VERSION 5.8 ;
BUSBITCHARS "[]" ;
DIVIDERCHAR "/" ;
UNITS
    DATABASE MICRONS 1000 ;
END UNITS

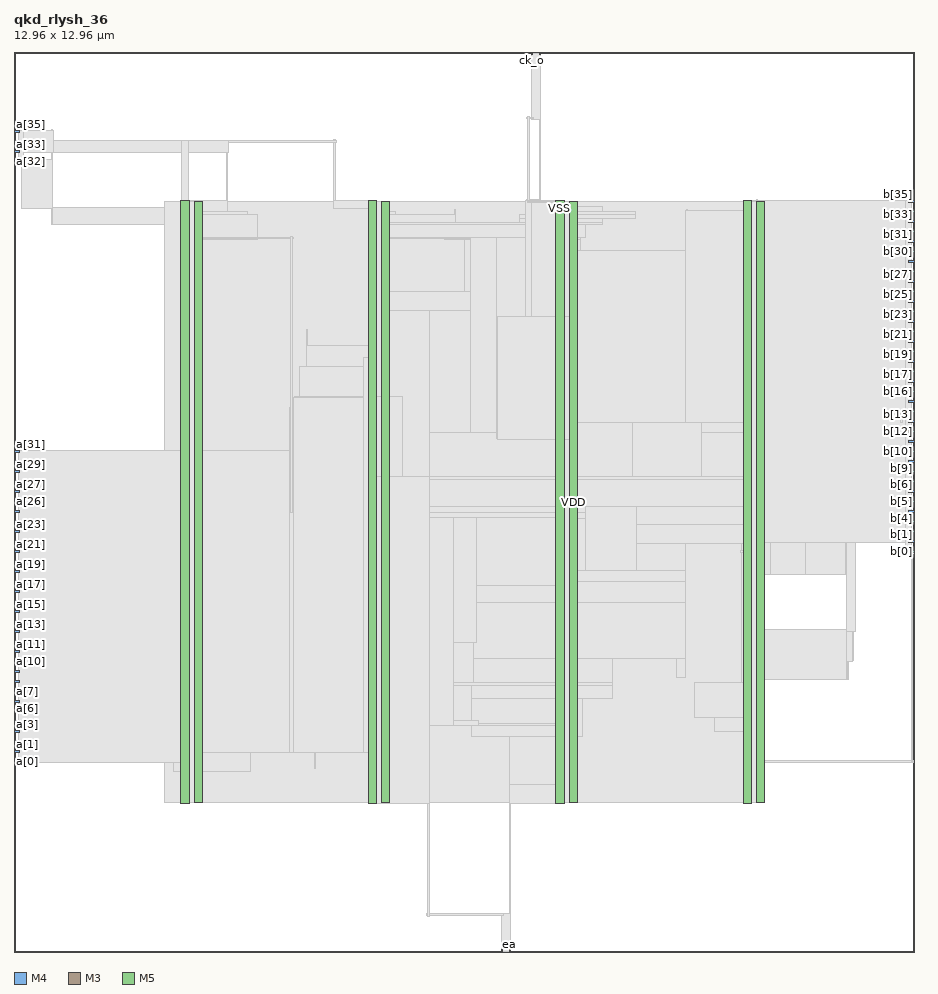
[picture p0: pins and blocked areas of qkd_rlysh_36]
MACRO qkd_rlysh_36
  FOREIGN qkd_rlysh_36 0 0 ;
  CLASS BLOCK ;
  SIZE 12.96 BY 12.96 ;
  PIN a[0]
    DIRECTION INPUT ;
    USE SIGNAL ;
    PORT
      LAYER M4 ;
        RECT  0 2.736 0.084 2.76 ;
    END
  END a[0]
  PIN a[10]
    DIRECTION INPUT ;
    USE SIGNAL ;
    PORT
      LAYER M4 ;
        RECT  0 4.176 0.084 4.2 ;
    END
  END a[10]
  PIN a[11]
    DIRECTION INPUT ;
    USE SIGNAL ;
    PORT
      LAYER M4 ;
        RECT  0 4.32 0.084 4.344 ;
    END
  END a[11]
  PIN a[12]
    DIRECTION INPUT ;
    USE SIGNAL ;
    PORT
      LAYER M4 ;
        RECT  0 4.464 0.084 4.488 ;
    END
  END a[12]
  PIN a[13]
    DIRECTION INPUT ;
    USE SIGNAL ;
    PORT
      LAYER M4 ;
        RECT  0 4.608 0.084 4.632 ;
    END
  END a[13]
  PIN a[14]
    DIRECTION INPUT ;
    USE SIGNAL ;
    PORT
      LAYER M4 ;
        RECT  0 4.752 0.084 4.776 ;
    END
  END a[14]
  PIN a[15]
    DIRECTION INPUT ;
    USE SIGNAL ;
    PORT
      LAYER M4 ;
        RECT  0 4.896 0.084 4.92 ;
    END
  END a[15]
  PIN a[16]
    DIRECTION INPUT ;
    USE SIGNAL ;
    PORT
      LAYER M4 ;
        RECT  0 5.04 0.084 5.064 ;
    END
  END a[16]
  PIN a[17]
    DIRECTION INPUT ;
    USE SIGNAL ;
    PORT
      LAYER M4 ;
        RECT  0 5.184 0.084 5.208 ;
    END
  END a[17]
  PIN a[18]
    DIRECTION INPUT ;
    USE SIGNAL ;
    PORT
      LAYER M4 ;
        RECT  0 5.328 0.084 5.352 ;
    END
  END a[18]
  PIN a[19]
    DIRECTION INPUT ;
    USE SIGNAL ;
    PORT
      LAYER M4 ;
        RECT  0 5.472 0.084 5.496 ;
    END
  END a[19]
  PIN a[1]
    DIRECTION INPUT ;
    USE SIGNAL ;
    PORT
      LAYER M4 ;
        RECT  0 2.88 0.084 2.904 ;
    END
  END a[1]
  PIN a[20]
    DIRECTION INPUT ;
    USE SIGNAL ;
    PORT
      LAYER M4 ;
        RECT  0 5.616 0.084 5.64 ;
    END
  END a[20]
  PIN a[21]
    DIRECTION INPUT ;
    USE SIGNAL ;
    PORT
      LAYER M4 ;
        RECT  0 5.76 0.084 5.784 ;
    END
  END a[21]
  PIN a[22]
    DIRECTION INPUT ;
    USE SIGNAL ;
    PORT
      LAYER M4 ;
        RECT  0 5.904 0.084 5.928 ;
    END
  END a[22]
  PIN a[23]
    DIRECTION INPUT ;
    USE SIGNAL ;
    PORT
      LAYER M4 ;
        RECT  0 6.048 0.084 6.072 ;
    END
  END a[23]
  PIN a[24]
    DIRECTION INPUT ;
    USE SIGNAL ;
    PORT
      LAYER M4 ;
        RECT  0 6.192 0.084 6.216 ;
    END
  END a[24]
  PIN a[25]
    DIRECTION INPUT ;
    USE SIGNAL ;
    PORT
      LAYER M4 ;
        RECT  0 6.336 0.084 6.36 ;
    END
  END a[25]
  PIN a[26]
    DIRECTION INPUT ;
    USE SIGNAL ;
    PORT
      LAYER M4 ;
        RECT  0 6.48 0.084 6.504 ;
    END
  END a[26]
  PIN a[27]
    DIRECTION INPUT ;
    USE SIGNAL ;
    PORT
      LAYER M4 ;
        RECT  0 6.624 0.084 6.648 ;
    END
  END a[27]
  PIN a[28]
    DIRECTION INPUT ;
    USE SIGNAL ;
    PORT
      LAYER M4 ;
        RECT  0 6.768 0.084 6.792 ;
    END
  END a[28]
  PIN a[29]
    DIRECTION INPUT ;
    USE SIGNAL ;
    PORT
      LAYER M4 ;
        RECT  0 6.912 0.084 6.936 ;
    END
  END a[29]
  PIN a[2]
    DIRECTION INPUT ;
    USE SIGNAL ;
    PORT
      LAYER M4 ;
        RECT  0 3.024 0.084 3.048 ;
    END
  END a[2]
  PIN a[30]
    DIRECTION INPUT ;
    USE SIGNAL ;
    PORT
      LAYER M4 ;
        RECT  0 7.056 0.084 7.08 ;
    END
  END a[30]
  PIN a[31]
    DIRECTION INPUT ;
    USE SIGNAL ;
    PORT
      LAYER M4 ;
        RECT  0 7.2 0.084 7.224 ;
    END
  END a[31]
  PIN a[32]
    DIRECTION INPUT ;
    USE SIGNAL ;
    PORT
      LAYER M4 ;
        RECT  0 11.376 0.084 11.4 ;
    END
  END a[32]
  PIN a[33]
    DIRECTION INPUT ;
    USE SIGNAL ;
    PORT
      LAYER M4 ;
        RECT  0 11.52 0.084 11.544 ;
    END
  END a[33]
  PIN a[34]
    DIRECTION INPUT ;
    USE SIGNAL ;
    PORT
      LAYER M4 ;
        RECT  0 11.664 0.084 11.688 ;
    END
  END a[34]
  PIN a[35]
    DIRECTION INPUT ;
    USE SIGNAL ;
    PORT
      LAYER M4 ;
        RECT  0 11.808 0.084 11.832 ;
    END
  END a[35]
  PIN a[3]
    DIRECTION INPUT ;
    USE SIGNAL ;
    PORT
      LAYER M4 ;
        RECT  0 3.168 0.084 3.192 ;
    END
  END a[3]
  PIN a[4]
    DIRECTION INPUT ;
    USE SIGNAL ;
    PORT
      LAYER M4 ;
        RECT  0 3.312 0.084 3.336 ;
    END
  END a[4]
  PIN a[5]
    DIRECTION INPUT ;
    USE SIGNAL ;
    PORT
      LAYER M4 ;
        RECT  0 3.456 0.084 3.48 ;
    END
  END a[5]
  PIN a[6]
    DIRECTION INPUT ;
    USE SIGNAL ;
    PORT
      LAYER M4 ;
        RECT  0 3.6 0.084 3.624 ;
    END
  END a[6]
  PIN a[7]
    DIRECTION INPUT ;
    USE SIGNAL ;
    PORT
      LAYER M4 ;
        RECT  0 3.744 0.084 3.768 ;
    END
  END a[7]
  PIN a[8]
    DIRECTION INPUT ;
    USE SIGNAL ;
    PORT
      LAYER M4 ;
        RECT  0 3.888 0.084 3.912 ;
    END
  END a[8]
  PIN a[9]
    DIRECTION INPUT ;
    USE SIGNAL ;
    PORT
      LAYER M4 ;
        RECT  0 4.032 0.084 4.056 ;
    END
  END a[9]
  PIN b[0]
    DIRECTION OUTPUT ;
    USE SIGNAL ;
    PORT
      LAYER M4 ;
        RECT  12.876 5.76 12.96 5.784 ;
    END
  END b[0]
  PIN b[10]
    DIRECTION OUTPUT ;
    USE SIGNAL ;
    PORT
      LAYER M4 ;
        RECT  12.876 7.2 12.96 7.224 ;
    END
  END b[10]
  PIN b[11]
    DIRECTION OUTPUT ;
    USE SIGNAL ;
    PORT
      LAYER M4 ;
        RECT  12.876 7.344 12.96 7.368 ;
    END
  END b[11]
  PIN b[12]
    DIRECTION OUTPUT ;
    USE SIGNAL ;
    PORT
      LAYER M4 ;
        RECT  12.876 7.488 12.96 7.512 ;
    END
  END b[12]
  PIN b[13]
    DIRECTION OUTPUT ;
    USE SIGNAL ;
    PORT
      LAYER M4 ;
        RECT  12.876 7.632 12.96 7.656 ;
    END
  END b[13]
  PIN b[14]
    DIRECTION OUTPUT ;
    USE SIGNAL ;
    PORT
      LAYER M4 ;
        RECT  12.876 7.776 12.96 7.8 ;
    END
  END b[14]
  PIN b[15]
    DIRECTION OUTPUT ;
    USE SIGNAL ;
    PORT
      LAYER M4 ;
        RECT  12.876 7.92 12.96 7.944 ;
    END
  END b[15]
  PIN b[16]
    DIRECTION OUTPUT ;
    USE SIGNAL ;
    PORT
      LAYER M4 ;
        RECT  12.876 8.064 12.96 8.088 ;
    END
  END b[16]
  PIN b[17]
    DIRECTION OUTPUT ;
    USE SIGNAL ;
    PORT
      LAYER M4 ;
        RECT  12.876 8.208 12.96 8.232 ;
    END
  END b[17]
  PIN b[18]
    DIRECTION OUTPUT ;
    USE SIGNAL ;
    PORT
      LAYER M4 ;
        RECT  12.876 8.352 12.96 8.376 ;
    END
  END b[18]
  PIN b[19]
    DIRECTION OUTPUT ;
    USE SIGNAL ;
    PORT
      LAYER M4 ;
        RECT  12.876 8.496 12.96 8.52 ;
    END
  END b[19]
  PIN b[1]
    DIRECTION OUTPUT ;
    USE SIGNAL ;
    PORT
      LAYER M4 ;
        RECT  12.876 5.904 12.96 5.928 ;
    END
  END b[1]
  PIN b[20]
    DIRECTION OUTPUT ;
    USE SIGNAL ;
    PORT
      LAYER M4 ;
        RECT  12.876 8.64 12.96 8.664 ;
    END
  END b[20]
  PIN b[21]
    DIRECTION OUTPUT ;
    USE SIGNAL ;
    PORT
      LAYER M4 ;
        RECT  12.876 8.784 12.96 8.808 ;
    END
  END b[21]
  PIN b[22]
    DIRECTION OUTPUT ;
    USE SIGNAL ;
    PORT
      LAYER M4 ;
        RECT  12.876 8.928 12.96 8.952 ;
    END
  END b[22]
  PIN b[23]
    DIRECTION OUTPUT ;
    USE SIGNAL ;
    PORT
      LAYER M4 ;
        RECT  12.876 9.072 12.96 9.096 ;
    END
  END b[23]
  PIN b[24]
    DIRECTION OUTPUT ;
    USE SIGNAL ;
    PORT
      LAYER M4 ;
        RECT  12.876 9.216 12.96 9.24 ;
    END
  END b[24]
  PIN b[25]
    DIRECTION OUTPUT ;
    USE SIGNAL ;
    PORT
      LAYER M4 ;
        RECT  12.876 9.36 12.96 9.384 ;
    END
  END b[25]
  PIN b[26]
    DIRECTION OUTPUT ;
    USE SIGNAL ;
    PORT
      LAYER M4 ;
        RECT  12.876 9.504 12.96 9.528 ;
    END
  END b[26]
  PIN b[27]
    DIRECTION OUTPUT ;
    USE SIGNAL ;
    PORT
      LAYER M4 ;
        RECT  12.876 9.648 12.96 9.672 ;
    END
  END b[27]
  PIN b[28]
    DIRECTION OUTPUT ;
    USE SIGNAL ;
    PORT
      LAYER M4 ;
        RECT  12.876 9.792 12.96 9.816 ;
    END
  END b[28]
  PIN b[29]
    DIRECTION OUTPUT ;
    USE SIGNAL ;
    PORT
      LAYER M4 ;
        RECT  12.876 9.936 12.96 9.96 ;
    END
  END b[29]
  PIN b[2]
    DIRECTION OUTPUT ;
    USE SIGNAL ;
    PORT
      LAYER M4 ;
        RECT  12.876 6.048 12.96 6.072 ;
    END
  END b[2]
  PIN b[30]
    DIRECTION OUTPUT ;
    USE SIGNAL ;
    PORT
      LAYER M4 ;
        RECT  12.876 10.08 12.96 10.104 ;
    END
  END b[30]
  PIN b[31]
    DIRECTION OUTPUT ;
    USE SIGNAL ;
    PORT
      LAYER M4 ;
        RECT  12.876 10.224 12.96 10.248 ;
    END
  END b[31]
  PIN b[32]
    DIRECTION OUTPUT ;
    USE SIGNAL ;
    PORT
      LAYER M4 ;
        RECT  12.876 10.368 12.96 10.392 ;
    END
  END b[32]
  PIN b[33]
    DIRECTION OUTPUT ;
    USE SIGNAL ;
    PORT
      LAYER M4 ;
        RECT  12.876 10.512 12.96 10.536 ;
    END
  END b[33]
  PIN b[34]
    DIRECTION OUTPUT ;
    USE SIGNAL ;
    PORT
      LAYER M4 ;
        RECT  12.876 10.656 12.96 10.68 ;
    END
  END b[34]
  PIN b[35]
    DIRECTION OUTPUT ;
    USE SIGNAL ;
    PORT
      LAYER M4 ;
        RECT  12.876 10.8 12.96 10.824 ;
    END
  END b[35]
  PIN b[3]
    DIRECTION OUTPUT ;
    USE SIGNAL ;
    PORT
      LAYER M4 ;
        RECT  12.876 6.192 12.96 6.216 ;
    END
  END b[3]
  PIN b[4]
    DIRECTION OUTPUT ;
    USE SIGNAL ;
    PORT
      LAYER M4 ;
        RECT  12.876 6.336 12.96 6.36 ;
    END
  END b[4]
  PIN b[5]
    DIRECTION OUTPUT ;
    USE SIGNAL ;
    PORT
      LAYER M4 ;
        RECT  12.876 6.48 12.96 6.504 ;
    END
  END b[5]
  PIN b[6]
    DIRECTION OUTPUT ;
    USE SIGNAL ;
    PORT
      LAYER M4 ;
        RECT  12.876 6.624 12.96 6.648 ;
    END
  END b[6]
  PIN b[7]
    DIRECTION OUTPUT ;
    USE SIGNAL ;
    PORT
      LAYER M4 ;
        RECT  12.876 6.768 12.96 6.792 ;
    END
  END b[7]
  PIN b[8]
    DIRECTION OUTPUT ;
    USE SIGNAL ;
    PORT
      LAYER M4 ;
        RECT  12.876 6.912 12.96 6.936 ;
    END
  END b[8]
  PIN b[9]
    DIRECTION OUTPUT ;
    USE SIGNAL ;
    PORT
      LAYER M4 ;
        RECT  12.876 7.056 12.96 7.08 ;
    END
  END b[9]
  PIN ck_o
    DIRECTION OUTPUT ;
    USE SIGNAL ;
    PORT
      LAYER M3 ;
        RECT  7.452 12.923 7.47 12.96 ;
    END
  END ck_o
  PIN ckf
    DIRECTION INPUT ;
    USE SIGNAL ;
    PORT
      LAYER M3 ;
        RECT  7.02 0 7.038 0.037 ;
    END
  END ckf
  PIN ea
    DIRECTION INPUT ;
    USE SIGNAL ;
    PORT
      LAYER M3 ;
        RECT  7.128 0 7.146 0.037 ;
    END
  END ea
  PIN eb
    DIRECTION OUTPUT ;
    USE SIGNAL ;
    PORT
      LAYER M3 ;
        RECT  7.56 12.923 7.578 12.96 ;
    END
  END eb
  PIN VDD
    DIRECTION INOUT ;
    USE POWER ;
    PORT
      LAYER M5 ;
        RECT  10.692 2.151 10.812 10.809 ;
        RECT  7.992 2.151 8.112 10.809 ;
        RECT  5.292 2.151 5.412 10.809 ;
        RECT  2.592 2.151 2.712 10.809 ;
    END
  END VDD
  PIN VSS
    DIRECTION INOUT ;
    USE GROUND ;
    PORT
      LAYER M5 ;
        RECT  10.5 2.137 10.62 10.823 ;
        RECT  7.8 2.137 7.92 10.823 ;
        RECT  5.1 2.137 5.22 10.823 ;
        RECT  2.4 2.137 2.52 10.823 ;
    END
  END VSS
  OBS
    LAYER RVTN ;
     RECT  2.16 2.16 10.8 2.295 ;
     RECT  2.16 2.565 10.8 2.835 ;
     RECT  2.16 3.105 10.8 3.375 ;
     RECT  2.16 3.645 10.8 3.915 ;
     RECT  2.16 4.185 10.8 4.455 ;
     RECT  2.16 4.725 10.8 4.995 ;
     RECT  2.16 5.265 10.8 5.535 ;
     RECT  2.16 5.805 10.8 6.075 ;
     RECT  2.16 6.345 10.8 6.615 ;
     RECT  2.16 6.885 10.8 7.155 ;
     RECT  2.16 7.425 10.8 7.695 ;
     RECT  2.16 7.965 10.8 8.235 ;
     RECT  2.16 8.505 10.8 8.775 ;
     RECT  2.16 9.045 10.8 9.315 ;
     RECT  2.16 9.585 10.8 9.855 ;
     RECT  2.16 10.125 10.8 10.395 ;
     RECT  2.16 10.665 10.8 10.8 ;
    LAYER RVTP ;
     RECT  2.16 2.295 10.8 2.565 ;
     RECT  2.16 2.835 10.8 3.105 ;
     RECT  2.16 3.375 10.8 3.645 ;
     RECT  2.16 3.915 10.8 4.185 ;
     RECT  2.16 4.455 10.8 4.725 ;
     RECT  2.16 4.995 10.8 5.265 ;
     RECT  2.16 5.535 10.8 5.805 ;
     RECT  2.16 6.075 10.8 6.345 ;
     RECT  2.16 6.615 10.8 6.885 ;
     RECT  2.16 7.155 10.8 7.425 ;
     RECT  2.16 7.695 10.8 7.965 ;
     RECT  2.16 8.235 10.8 8.505 ;
     RECT  2.16 8.775 10.8 9.045 ;
     RECT  2.16 9.315 10.8 9.585 ;
     RECT  2.16 9.855 10.8 10.125 ;
     RECT  2.16 10.395 10.8 10.665 ;
    LAYER M1 ;
     RECT  2.16 2.151 10.8 10.809 ;
    LAYER M2 ;
     RECT  0.103 10.71 0.535 10.728 ;
     RECT  0.103 5.274 2.16 5.292 ;
     RECT  0.535 6.822 2.16 6.84 ;
     RECT  0.535 10.476 2.16 10.728 ;
     RECT  2.16 2.151 10.8 10.809 ;
     RECT  10.8 2.421 10.812 10.539 ;
     RECT  10.812 5.436 10.895 10.494 ;
     RECT  10.895 5.436 11.399 9.504 ;
     RECT  11.399 5.436 11.975 6.102 ;
     RECT  10.812 3.924 12.011 4.644 ;
     RECT  11.399 6.966 12.011 9.504 ;
     RECT  10.895 10.368 12.011 10.494 ;
     RECT  11.975 5.436 12.047 5.454 ;
     RECT  12.011 6.966 12.047 7.722 ;
     RECT  12.011 8.676 12.047 9.504 ;
     RECT  12.011 4.194 12.083 4.644 ;
     RECT  12.047 9.396 12.083 9.414 ;
     RECT  12.083 4.626 12.119 4.644 ;
     RECT  12.047 6.966 12.875 6.984 ;
     RECT  10.812 2.736 12.947 2.754 ;
     RECT  12.847 5.742 12.947 5.76 ;
    LAYER M3 ;
     RECT  7.02 0.012 7.146 0.557 ;
     RECT  7.128 0.557 7.146 2.143 ;
     RECT  2.415 2.143 2.505 2.413 ;
     RECT  5.115 2.143 5.205 2.413 ;
     RECT  7.128 2.143 7.905 2.413 ;
     RECT  10.515 2.143 10.605 2.413 ;
     RECT  2.415 2.413 2.697 2.605 ;
     RECT  4.32 2.641 4.338 2.875 ;
     RECT  4.14 2.875 4.338 3.065 ;
     RECT  4.248 3.065 4.338 3.109 ;
     RECT  5.115 2.413 5.397 3.109 ;
     RECT  7.128 2.413 8.097 3.109 ;
     RECT  10.515 2.413 10.797 3.181 ;
     RECT  4.248 3.109 5.814 3.335 ;
     RECT  10.08 3.181 10.797 3.379 ;
     RECT  2.304 2.605 3.402 3.488 ;
     RECT  6.588 3.109 8.19 3.649 ;
     RECT  2.34 3.488 3.402 3.749 ;
     RECT  6.588 3.649 8.622 3.835 ;
     RECT  0.144 3.739 0.162 3.869 ;
     RECT  6.3 3.835 8.622 3.875 ;
     RECT  9.792 3.379 10.797 3.875 ;
     RECT  4.284 3.335 5.397 4.109 ;
     RECT  11.988 3.919 12.006 4.189 ;
     RECT  6.624 3.875 8.622 4.225 ;
     RECT  9.54 3.955 9.666 4.225 ;
     RECT  2.34 3.749 3.258 4.315 ;
     RECT  11.988 4.189 12.078 4.621 ;
     RECT  2.304 4.315 3.258 4.801 ;
     RECT  4.32 4.109 5.397 4.801 ;
     RECT  2.304 4.801 3.51 4.919 ;
     RECT  4.32 4.801 5.526 5.029 ;
     RECT  6.624 4.225 9.666 5.029 ;
     RECT  0.108 4.891 0.126 5.227 ;
     RECT  0.108 5.227 0.162 5.297 ;
     RECT  4.32 5.029 9.666 5.341 ;
     RECT  4.176 5.341 9.666 5.495 ;
     RECT  12.924 2.731 12.942 5.737 ;
     RECT  2.304 4.919 3.258 5.765 ;
     RECT  12.852 5.737 12.942 5.765 ;
     RECT  12.852 5.765 12.87 5.789 ;
     RECT  8.964 5.495 9.666 5.881 ;
     RECT  10.476 3.875 10.797 5.881 ;
     RECT  11.988 4.621 12.114 6.076 ;
     RECT  8.964 5.881 10.797 6.151 ;
     RECT  11.952 6.076 12.114 6.151 ;
     RECT  4.176 5.495 8.226 6.241 ;
     RECT  0.144 5.297 0.162 6.283 ;
     RECT  2.412 5.765 3.258 6.305 ;
     RECT  2.415 6.305 3.258 6.331 ;
     RECT  4.104 6.241 8.226 6.331 ;
     RECT  2.415 6.331 8.226 6.421 ;
     RECT  8.964 6.151 12.114 6.421 ;
     RECT  0.144 6.283 0.198 6.509 ;
     RECT  0.18 6.509 0.198 6.653 ;
     RECT  2.415 6.421 12.114 6.809 ;
     RECT  4.104 6.809 12.114 6.845 ;
     RECT  0.54 6.817 0.558 6.941 ;
     RECT  12.852 6.907 12.87 6.989 ;
     RECT  2.415 6.809 3.366 7.051 ;
     RECT  2.304 7.051 3.366 7.088 ;
     RECT  2.415 7.088 3.366 7.115 ;
     RECT  9.9 6.845 12.114 7.483 ;
     RECT  9.9 7.483 12.69 7.619 ;
     RECT  10.515 7.619 12.69 7.661 ;
     RECT  10.515 7.661 12.042 7.805 ;
     RECT  4.104 6.845 8.91 7.897 ;
     RECT  4.032 7.897 8.91 7.997 ;
     RECT  10.515 7.805 10.89 8.381 ;
     RECT  4.104 7.997 8.91 8.429 ;
     RECT  4.212 8.429 8.91 8.735 ;
     RECT  5.115 8.735 8.91 8.851 ;
     RECT  4.212 8.735 4.23 8.969 ;
     RECT  5.115 8.851 9.054 9.013 ;
     RECT  5.115 9.013 9.162 9.041 ;
     RECT  8.892 9.041 9.162 9.113 ;
     RECT  10.515 8.381 10.818 9.113 ;
     RECT  12.78 8.539 12.798 9.341 ;
     RECT  11.988 7.805 12.042 9.391 ;
     RECT  5.115 9.041 8.154 9.509 ;
     RECT  11.988 9.391 12.078 9.533 ;
     RECT  8.892 9.113 8.982 9.545 ;
     RECT  8.964 9.545 8.982 9.815 ;
     RECT  12.024 9.533 12.078 9.821 ;
     RECT  10.515 9.113 10.797 9.925 ;
     RECT  10.515 9.925 10.89 9.965 ;
     RECT  10.515 9.965 10.818 10.253 ;
     RECT  2.415 7.115 2.697 10.267 ;
     RECT  6.48 9.509 8.154 10.267 ;
     RECT  5.115 9.509 5.397 10.291 ;
     RECT  6.192 10.267 8.154 10.291 ;
     RECT  5.115 10.291 8.226 10.471 ;
     RECT  5.115 10.471 8.478 10.499 ;
     RECT  11.988 10.357 12.006 10.541 ;
     RECT  10.515 10.253 10.797 10.547 ;
     RECT  7.272 10.499 8.478 10.561 ;
     RECT  2.415 10.267 3.51 10.625 ;
     RECT  5.115 10.499 6.354 10.625 ;
     RECT  7.272 10.561 8.946 10.625 ;
     RECT  2.415 10.625 3.366 10.661 ;
     RECT  5.115 10.625 5.49 10.661 ;
     RECT  7.38 10.625 8.946 10.661 ;
     RECT  9.684 10.291 9.702 10.685 ;
     RECT  6.336 10.625 6.354 10.697 ;
     RECT  0.54 10.471 0.558 10.705 ;
     RECT  5.115 10.661 5.205 10.705 ;
     RECT  7.38 10.661 8.478 10.733 ;
     RECT  2.415 10.661 3.078 10.817 ;
     RECT  4.608 10.705 5.205 10.817 ;
     RECT  7.38 10.733 7.905 10.817 ;
     RECT  10.515 10.547 10.71 10.817 ;
     RECT  7.38 10.817 7.578 10.829 ;
     RECT  10.692 10.817 10.71 10.829 ;
     RECT  0.108 10.705 0.558 11.405 ;
     RECT  3.06 10.817 3.078 11.549 ;
     RECT  4.608 10.817 4.626 11.693 ;
     RECT  0.54 11.405 0.558 11.837 ;
     RECT  7.56 10.829 7.578 11.995 ;
     RECT  7.452 11.995 7.578 12.941 ;
    LAYER M4 ;
     RECT  0.06 11.376 0.137 11.832 ;
     RECT  0.137 11.52 0.569 11.832 ;
     RECT  0.06 2.736 2.408 7.224 ;
     RECT  0.569 11.52 2.408 11.688 ;
     RECT  2.408 2.148 2.512 11.688 ;
     RECT  2.512 2.418 2.704 10.542 ;
     RECT  2.512 11.52 3.089 11.688 ;
     RECT  2.704 2.88 3.973 7.224 ;
     RECT  2.704 10.272 4.019 10.296 ;
     RECT  3.973 2.88 4.021 7.848 ;
     RECT  3.089 11.664 4.637 11.688 ;
     RECT  4.021 2.88 5.029 7.992 ;
     RECT  5.029 2.88 5.108 8.568 ;
     RECT  5.108 2.148 5.212 10.812 ;
     RECT  5.212 2.418 5.404 10.542 ;
     RECT  5.404 3.264 5.987 9.24 ;
     RECT  5.987 3.264 6.329 6.264 ;
     RECT  5.987 7.488 6.577 9.24 ;
     RECT  5.404 10.272 6.577 10.296 ;
     RECT  6.329 4.464 6.653 6.264 ;
     RECT  6.329 3.264 6.689 3.336 ;
     RECT  6.577 7.488 6.949 10.296 ;
     RECT  5.941 0.528 7.049 0.552 ;
     RECT  6.949 7.392 7.369 10.296 ;
     RECT  7.369 7.392 7.453 10.824 ;
     RECT  7.381 12 7.481 12.024 ;
     RECT  6.689 3.264 7.808 3.288 ;
     RECT  6.653 5.28 7.808 6.264 ;
     RECT  7.453 7.392 7.808 10.812 ;
     RECT  7.808 2.148 7.912 10.812 ;
     RECT  7.912 2.418 8.104 10.542 ;
     RECT  8.104 7.632 9.673 10.104 ;
     RECT  10.465 5.76 10.508 5.784 ;
     RECT  9.673 7.632 10.508 10.68 ;
     RECT  10.508 2.148 10.612 10.812 ;
     RECT  10.612 2.418 10.681 10.812 ;
     RECT  10.681 2.418 10.804 10.824 ;
     RECT  10.804 5.904 12.841 10.824 ;
     RECT  12.841 5.76 12.924 10.824 ;
    LAYER M5 ;
     RECT  5.952 0.517 5.976 2.137 ;
     RECT  2.4 2.137 2.52 2.151 ;
     RECT  7.8 2.137 7.92 2.151 ;
     RECT  10.5 2.137 10.62 2.151 ;
     RECT  5.1 2.137 5.976 6.851 ;
     RECT  7.8 2.151 8.112 7.381 ;
     RECT  12.768 7.621 12.792 7.763 ;
     RECT  5.1 6.851 5.592 8.003 ;
     RECT  6.96 7.381 8.112 9.155 ;
     RECT  3.984 6.325 4.008 10.307 ;
     RECT  7.8 9.155 8.112 10.789 ;
     RECT  2.4 2.151 2.712 10.809 ;
     RECT  5.1 8.003 5.412 10.809 ;
     RECT  7.392 10.789 8.112 10.809 ;
     RECT  10.5 2.151 10.812 10.809 ;
     RECT  2.4 10.809 2.52 10.823 ;
     RECT  5.1 10.809 5.22 10.823 ;
     RECT  7.392 10.809 7.92 10.823 ;
     RECT  10.5 10.809 10.62 10.823 ;
     RECT  7.392 10.823 7.416 12.035 ;
  END
END qkd_rlysh_36
END LIBRARY
